One B-rep face of a CAD part: STEP entity #47.
In plain terms, the planar face has unit normal (1, 0, 0).
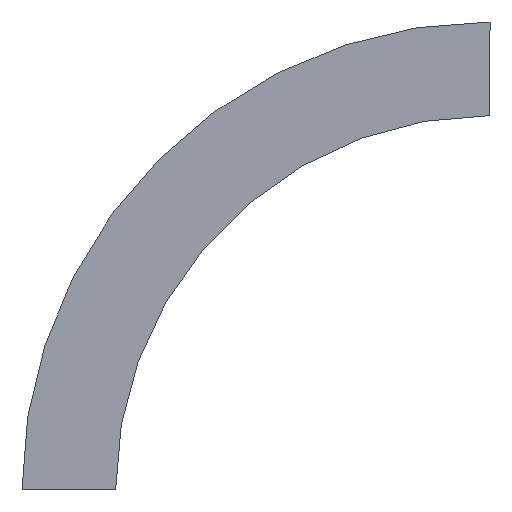
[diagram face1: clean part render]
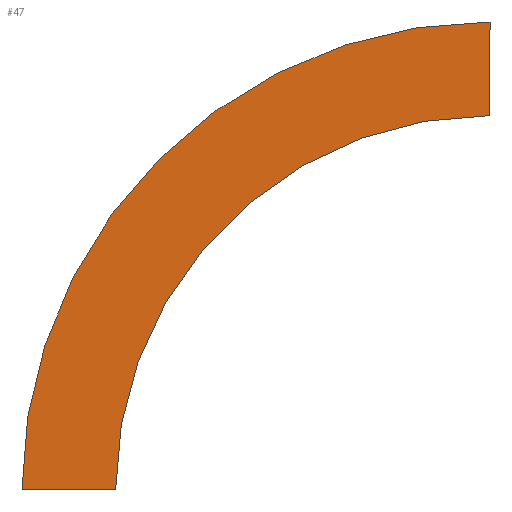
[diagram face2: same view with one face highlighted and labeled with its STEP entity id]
Its self-contained STEP definition (entity closure, numbers rounded to 3 decimals):
#35 = CARTESIAN_POINT ( 'NONE',  ( 0., 0., 0. ) ) ;
#39 = AXIS2_PLACEMENT_3D ( 'NONE', #104, #509, #511 ) ;
#47 = ADVANCED_FACE ( 'NONE', ( #102 ), #153, .T. ) ;
#49 = DIRECTION ( 'NONE',  ( 0., 0., -1. ) ) ;
#68 = AXIS2_PLACEMENT_3D ( 'NONE', #186, #231, #49 ) ;
#85 = EDGE_LOOP ( 'NONE', ( #130, #577, #108, #92 ) ) ;
#88 = CARTESIAN_POINT ( 'NONE',  ( 0., -300., 0. ) ) ;
#89 = CIRCLE ( 'NONE', #304, 300. ) ;
#92 = ORIENTED_EDGE ( 'NONE', *, *, #313, .T. ) ;
#102 = FACE_OUTER_BOUND ( 'NONE', #85, .T. ) ;
#104 = CARTESIAN_POINT ( 'NONE',  ( 0., -300., 0. ) ) ;
#108 = ORIENTED_EDGE ( 'NONE', *, *, #302, .F. ) ;
#130 = ORIENTED_EDGE ( 'NONE', *, *, #460, .T. ) ;
#153 = PLANE ( 'NONE',  #68 ) ;
#178 = VERTEX_POINT ( 'NONE', #248 ) ;
#186 = CARTESIAN_POINT ( 'NONE',  ( 0., 0., 0. ) ) ;
#210 = VECTOR ( 'NONE', #281, 1000. ) ;
#231 = DIRECTION ( 'NONE',  ( 1., 0., 0. ) ) ;
#239 = CARTESIAN_POINT ( 'NONE',  ( 0., -300., 375. ) ) ;
#248 = CARTESIAN_POINT ( 'NONE',  ( 0., 0., 0. ) ) ;
#254 = DIRECTION ( 'NONE',  ( 1., 0., 0. ) ) ;
#256 = LINE ( 'NONE', #377, #210 ) ;
#262 = VERTEX_POINT ( 'NONE', #564 ) ;
#281 = DIRECTION ( 'NONE',  ( 0., 0., 1. ) ) ;
#302 = EDGE_CURVE ( 'NONE', #178, #417, #89, .T. ) ;
#304 = AXIS2_PLACEMENT_3D ( 'NONE', #88, #254, #485 ) ;
#313 = EDGE_CURVE ( 'NONE', #178, #262, #575, .T. ) ;
#318 = CARTESIAN_POINT ( 'NONE',  ( 0., -300., 300. ) ) ;
#377 = CARTESIAN_POINT ( 'NONE',  ( 0., -300., 300. ) ) ;
#417 = VERTEX_POINT ( 'NONE', #318 ) ;
#460 = EDGE_CURVE ( 'NONE', #262, #573, #576, .T. ) ;
#481 = DIRECTION ( 'NONE',  ( 0., 1., 0. ) ) ;
#485 = DIRECTION ( 'NONE',  ( 0., 1., 0. ) ) ;
#509 = DIRECTION ( 'NONE',  ( 1., 0., 0. ) ) ;
#511 = DIRECTION ( 'NONE',  ( 0., 1., 0. ) ) ;
#550 = VECTOR ( 'NONE', #481, 1000. ) ;
#564 = CARTESIAN_POINT ( 'NONE',  ( 0., 75., 0. ) ) ;
#569 = EDGE_CURVE ( 'NONE', #417, #573, #256, .T. ) ;
#573 = VERTEX_POINT ( 'NONE', #239 ) ;
#575 = LINE ( 'NONE', #35, #550 ) ;
#576 = CIRCLE ( 'NONE', #39, 375. ) ;
#577 = ORIENTED_EDGE ( 'NONE', *, *, #569, .F. ) ;
